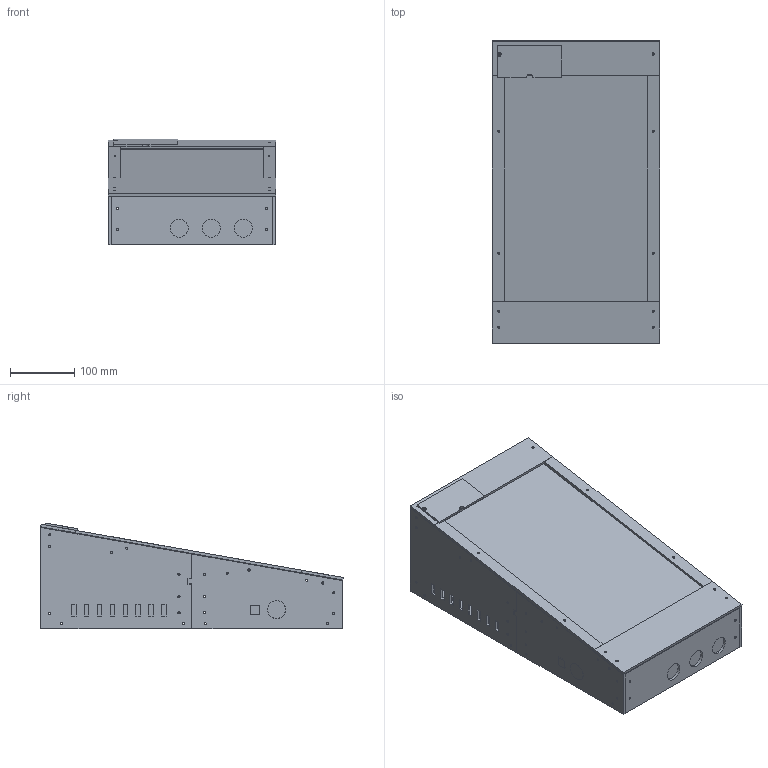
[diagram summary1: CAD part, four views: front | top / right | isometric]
STEP (ISO 10303-21) file: header records copied from the file, then geometry measured from it (millimetres).
FILE_DESCRIPTION(('Open CASCADE Model'),'2;1');
FILE_NAME('Open CASCADE Shape Model','2026-11-07T13:59:28',('Author'),( 'Open CASCADE'),'Open CASCADE STEP processor 7.8','Open CASCADE 7.8' ,'Unknown');
FILE_SCHEMA(('AUTOMOTIVE_DESIGN { 1 0 10303 214 1 1 1 1 }'));
Length unit declared in the file: millimetre
Products named in the file (65): Mini_VPin_Prototype_V1_9; left_front_wall; left_rear_wall; right_front_wall; right_rear_wall; front_button_panel; rear_vent_panel; corner_left_front_24; corner_left_front_56; corner_left_rear_24; corner_left_rear_128; corner_right_front_24; corner_right_front_56; corner_right_rear_24; corner_right_rear_128; splice_left; splice_right; floor_block_left_28; floor_block_left_218; floor_block_left_252; floor_block_left_442; floor_block_right_28; floor_block_right_218; floor_block_right_252; floor_block_right_442; bottom_front; bottom_rear; top_block_left_25; top_block_left_50; top_block_left_140; top_block_left_330; top_block_left_450; top_block_right_25; top_block_right_50; top_block_right_140; top_block_right_330; top_block_right_450; monitor_saddle_left_180; monitor_saddle_left_360; monitor_saddle_right_180 ...
Assembly tree (64 placements, depth 2):
  Mini_VPin_Prototype_V1_9
    left_front_wall
    left_rear_wall
    right_front_wall
    right_rear_wall
    front_button_panel
    rear_vent_panel
    corner_left_front_24
    corner_left_front_56
    corner_left_rear_24
    corner_left_rear_128
    corner_right_front_24
    corner_right_front_56
    corner_right_rear_24
    corner_right_rear_128
    splice_left
    splice_right
    floor_block_left_28
    floor_block_left_218
    floor_block_left_252
    floor_block_left_442
    floor_block_right_28
    floor_block_right_218
    floor_block_right_252
    floor_block_right_442
    bottom_front
    bottom_rear
    top_block_left_25
    top_block_left_50
    top_block_left_140
    top_block_left_330
    top_block_left_450
    top_block_right_25
    top_block_right_50
    top_block_right_140
    top_block_right_330
    top_block_right_450
    monitor_saddle_left_180
    monitor_saddle_left_360
    monitor_saddle_right_180
    monitor_saddle_right_360
    bezel_left_one_piece
    bezel_right_a1_a2
    front_cable_lid
    rear_control_deck
    control_hatch
    REFERENCE_monitor_12mm_envelope
    REFERENCE_PC_allowance_ports_face_front
    REFERENCE_0_front_button_110
    REFERENCE_1_front_button_160
    REFERENCE_2_front_button_210
    REFERENCE_3_left_flipper_barrel_D27.8
    REFERENCE_4_left_flipper_nut_D40_x5
    REFERENCE_5_left_flipper_body_and_wiring_40x40
    REFERENCE_6_left_assumed_MX_plate_stem_14.0
    REFERENCE_7_left_assumed_MX_body_clip_and_wiring_allowance
    REFERENCE_8_right_flipper_barrel_D27.8
    REFERENCE_9_right_flipper_nut_D40_x5
    REFERENCE_10_right_flipper_body_and_wiring_40x40
    REFERENCE_11_right_assumed_MX_plate_stem_14.0
Bounding box: 260.2 x 470.69 x 164.59 mm (x, y, z)
Volume: 7300620.2 mm3; surface area: 1392322 mm2
Topology: 64 solids, 64 shells, 1079 faces, 2757 edges, 1838 vertices
Faces by surface type: plane 874, cylinder 187, extrusion 16, cone 2
Full cylindrical faces by diameter (mm): 3.4 x152, 4.5 x4, 6 x2, 6.4 x2, 27.8 x2, 28 x5, 40 x2
Entity records: 80241 total; most frequent: CARTESIAN_POINT 22559, DIRECTION 10157, VECTOR 6773, LINE 6757, ORIENTED_EDGE 5514, PCURVE 5514, DEFINITIONAL_REPRESENTATION 5514, EDGE_CURVE 2757
One B-rep face of a CAD part: STEP entity #80080.
In plain terms, the planar face has unit normal (0, -0.174, 0.985).
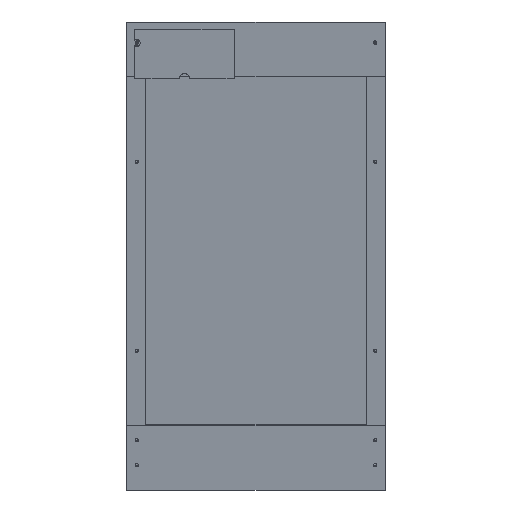
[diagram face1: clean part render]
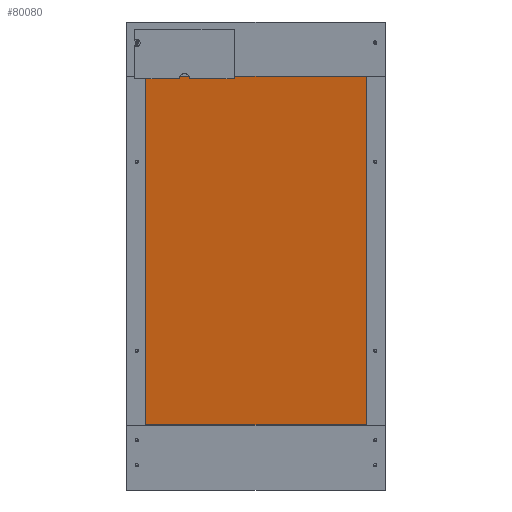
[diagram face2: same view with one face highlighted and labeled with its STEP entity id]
Its self-contained STEP definition (entity closure, numbers rounded to 3 decimals):
#79911 = PLANE('',#79912);
#79912 = AXIS2_PLACEMENT_3D('',#79913,#79914,#79915);
#79913 = CARTESIAN_POINT('',(18.1,64.,86.285));
#79914 = DIRECTION('',(-0.,1.,0.));
#79915 = DIRECTION('',(0.,0.,-1.));
#79939 = PLANE('',#79940);
#79940 = AXIS2_PLACEMENT_3D('',#79941,#79942,#79943);
#79941 = CARTESIAN_POINT('',(241.9,240.675,111.437));
#79942 = DIRECTION('',(1.,0.,0.));
#79943 = DIRECTION('',(-0.,0.,1.));
#79967 = PLANE('',#79968);
#79968 = AXIS2_PLACEMENT_3D('',#79969,#79970,#79971);
#79969 = CARTESIAN_POINT('',(18.1,417.349,136.59));
#79970 = DIRECTION('',(0.,-1.,0.));
#79971 = DIRECTION('',(0.,0.,1.));
#79993 = PLANE('',#79994);
#79994 = AXIS2_PLACEMENT_3D('',#79995,#79996,#79997);
#79995 = CARTESIAN_POINT('',(18.1,240.675,111.437));
#79996 = DIRECTION('',(1.,0.,0.));
#79997 = DIRECTION('',(-0.,0.,1.));
#80010 = VERTEX_POINT('',#80011);
#80011 = CARTESIAN_POINT('',(241.9,417.349,148.59));
#80032 = EDGE_CURVE('',#80033,#80010,#80035,.T.);
#80033 = VERTEX_POINT('',#80034);
#80034 = CARTESIAN_POINT('',(18.1,417.349,148.59));
#80035 = SURFACE_CURVE('',#80036,(#80040,#80047),.PCURVE_S1.);
#80036 = LINE('',#80037,#80038);
#80037 = CARTESIAN_POINT('',(18.1,417.349,148.59));
#80038 = VECTOR('',#80039,1.);
#80039 = DIRECTION('',(1.,0.,0.));
#80040 = PCURVE('',#79967,#80041);
#80041 = DEFINITIONAL_REPRESENTATION('',(#80042),#80046);
#80042 = LINE('',#80043,#80044);
#80043 = CARTESIAN_POINT('',(12.,0.));
#80044 = VECTOR('',#80045,1.);
#80045 = DIRECTION('',(0.,-1.));
#80046 = ( GEOMETRIC_REPRESENTATION_CONTEXT(2) 
PARAMETRIC_REPRESENTATION_CONTEXT() REPRESENTATION_CONTEXT('2D SPACE',''
  ) );
#80047 = PCURVE('',#80048,#80053);
#80048 = PLANE('',#80049);
#80049 = AXIS2_PLACEMENT_3D('',#80050,#80051,#80052);
#80050 = CARTESIAN_POINT('',(18.1,417.349,148.59));
#80051 = DIRECTION('',(0.,0.174,-0.985));
#80052 = DIRECTION('',(0.,-0.985,-0.174));
#80053 = DEFINITIONAL_REPRESENTATION('',(#80054),#80058);
#80054 = LINE('',#80055,#80056);
#80055 = CARTESIAN_POINT('',(0.,0.));
#80056 = VECTOR('',#80057,1.);
#80057 = DIRECTION('',(0.,-1.));
#80058 = ( GEOMETRIC_REPRESENTATION_CONTEXT(2) 
PARAMETRIC_REPRESENTATION_CONTEXT() REPRESENTATION_CONTEXT('2D SPACE',''
  ) );
#80080 = ADVANCED_FACE('',(#80081),#80048,.F.);
#80081 = FACE_BOUND('',#80082,.F.);
#80082 = EDGE_LOOP('',(#80083,#80084,#80107,#80130));
#80083 = ORIENTED_EDGE('',*,*,#80032,.T.);
#80084 = ORIENTED_EDGE('',*,*,#80085,.T.);
#80085 = EDGE_CURVE('',#80010,#80086,#80088,.T.);
#80086 = VERTEX_POINT('',#80087);
#80087 = CARTESIAN_POINT('',(241.9,64.,86.285));
#80088 = SURFACE_CURVE('',#80089,(#80093,#80100),.PCURVE_S1.);
#80089 = LINE('',#80090,#80091);
#80090 = CARTESIAN_POINT('',(241.9,417.349,148.59));
#80091 = VECTOR('',#80092,1.);
#80092 = DIRECTION('',(0.,-0.985,-0.174));
#80093 = PCURVE('',#80048,#80094);
#80094 = DEFINITIONAL_REPRESENTATION('',(#80095),#80099);
#80095 = LINE('',#80096,#80097);
#80096 = CARTESIAN_POINT('',(0.,-223.8));
#80097 = VECTOR('',#80098,1.);
#80098 = DIRECTION('',(1.,0.));
#80099 = ( GEOMETRIC_REPRESENTATION_CONTEXT(2) 
PARAMETRIC_REPRESENTATION_CONTEXT() REPRESENTATION_CONTEXT('2D SPACE',''
  ) );
#80100 = PCURVE('',#79939,#80101);
#80101 = DEFINITIONAL_REPRESENTATION('',(#80102),#80106);
#80102 = LINE('',#80103,#80104);
#80103 = CARTESIAN_POINT('',(37.152,-176.675));
#80104 = VECTOR('',#80105,1.);
#80105 = DIRECTION('',(-0.174,0.985));
#80106 = ( GEOMETRIC_REPRESENTATION_CONTEXT(2) 
PARAMETRIC_REPRESENTATION_CONTEXT() REPRESENTATION_CONTEXT('2D SPACE',''
  ) );
#80107 = ORIENTED_EDGE('',*,*,#80108,.F.);
#80108 = EDGE_CURVE('',#80109,#80086,#80111,.T.);
#80109 = VERTEX_POINT('',#80110);
#80110 = CARTESIAN_POINT('',(18.1,64.,86.285));
#80111 = SURFACE_CURVE('',#80112,(#80116,#80123),.PCURVE_S1.);
#80112 = LINE('',#80113,#80114);
#80113 = CARTESIAN_POINT('',(18.1,64.,86.285));
#80114 = VECTOR('',#80115,1.);
#80115 = DIRECTION('',(1.,0.,0.));
#80116 = PCURVE('',#80048,#80117);
#80117 = DEFINITIONAL_REPRESENTATION('',(#80118),#80122);
#80118 = LINE('',#80119,#80120);
#80119 = CARTESIAN_POINT('',(358.8,0.));
#80120 = VECTOR('',#80121,1.);
#80121 = DIRECTION('',(0.,-1.));
#80122 = ( GEOMETRIC_REPRESENTATION_CONTEXT(2) 
PARAMETRIC_REPRESENTATION_CONTEXT() REPRESENTATION_CONTEXT('2D SPACE',''
  ) );
#80123 = PCURVE('',#79911,#80124);
#80124 = DEFINITIONAL_REPRESENTATION('',(#80125),#80129);
#80125 = LINE('',#80126,#80127);
#80126 = CARTESIAN_POINT('',(0.,0.));
#80127 = VECTOR('',#80128,1.);
#80128 = DIRECTION('',(0.,-1.));
#80129 = ( GEOMETRIC_REPRESENTATION_CONTEXT(2) 
PARAMETRIC_REPRESENTATION_CONTEXT() REPRESENTATION_CONTEXT('2D SPACE',''
  ) );
#80130 = ORIENTED_EDGE('',*,*,#80131,.F.);
#80131 = EDGE_CURVE('',#80033,#80109,#80132,.T.);
#80132 = SURFACE_CURVE('',#80133,(#80137,#80144),.PCURVE_S1.);
#80133 = LINE('',#80134,#80135);
#80134 = CARTESIAN_POINT('',(18.1,417.349,148.59));
#80135 = VECTOR('',#80136,1.);
#80136 = DIRECTION('',(0.,-0.985,-0.174));
#80137 = PCURVE('',#80048,#80138);
#80138 = DEFINITIONAL_REPRESENTATION('',(#80139),#80143);
#80139 = LINE('',#80140,#80141);
#80140 = CARTESIAN_POINT('',(0.,0.));
#80141 = VECTOR('',#80142,1.);
#80142 = DIRECTION('',(1.,0.));
#80143 = ( GEOMETRIC_REPRESENTATION_CONTEXT(2) 
PARAMETRIC_REPRESENTATION_CONTEXT() REPRESENTATION_CONTEXT('2D SPACE',''
  ) );
#80144 = PCURVE('',#79993,#80145);
#80145 = DEFINITIONAL_REPRESENTATION('',(#80146),#80150);
#80146 = LINE('',#80147,#80148);
#80147 = CARTESIAN_POINT('',(37.152,-176.675));
#80148 = VECTOR('',#80149,1.);
#80149 = DIRECTION('',(-0.174,0.985));
#80150 = ( GEOMETRIC_REPRESENTATION_CONTEXT(2) 
PARAMETRIC_REPRESENTATION_CONTEXT() REPRESENTATION_CONTEXT('2D SPACE',''
  ) );
